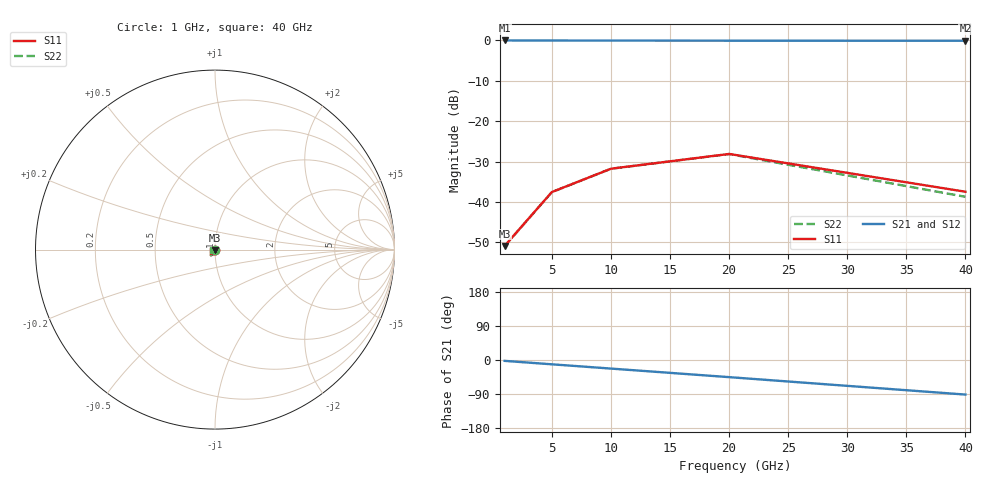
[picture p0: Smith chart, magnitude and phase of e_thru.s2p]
! Generated by circuitRF - EM: EMerge
! circuitRF-EM setup: g_thru_sheets
! circuitRF-EM layout: thru/layout/thru.clay
! circuitRF-EM written: 2026-11-04 17:22:48Z
! circuitRF-EM geometry: 4bac5df9cd719ece
! circuitRF-EM mesh: ae32805cddc33b92
! circuitRF-EM ports: e0915e1a10e1aaad
! circuitRF-EM model: EMerge 3.0.0b2
! Port[1] = port/1
! Port[2] = port/2
! circuitRF-EM port 1: 'port/1' from 'airbox/zmin' to 'Metal1/1', lumped, 50 Ohm
! circuitRF-EM port 2: 'port/2' from 'airbox/zmin' to 'Metal1/1', lumped, 50 Ohm
! circuitRF-EM 3D mesh: 2539 tetrahedra, element order 2
! circuitRF-EM 3D operating temperature: 20 C
! circuitRF-EM 3D run: preset Standard; 2539 tetrahedra; 17990 unknowns; 5 frequency sample(s)
! circuitRF-EM 3D run cost: wall 3 s; EMerge peak memory 1.2 GB
! circuitRF-EM 3D DC row: circuitRF conduction solve of the conductors, 368 elements, 0.17 s; ports as terminal pairs
! circuitRF-EM: re-running the EM setup rewrites this file. If circuitRF reports it as stale, the layout's cross-section changed after this file was written.
# GHz S RI R 50
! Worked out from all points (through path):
!   5 points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, 1 GHz to 40 GHz, reference 50 ohm
!   highest |S21| = 0.00 dB at 1 GHz (marker M1); lowest = -0.1 dB at 40 GHz (marker M2)
!   lowest |S11| = -50.9 dB at 1 GHz (marker M3), VSWR 1.01, Z = 50.2 - j0.23 ohm
!   |S11| at or under -10 dB: start of sweep to end of sweep
!   |S22| runs from -50.9 to -28.1 dB; largest |S21 - S12| = 4.9e-05
1  0.00171 -0.00229  0.9988 -0.04  0.9989 -0.04  0.00168 -0.00229
5  0.00082 -0.0132  0.9783 -0.1966  0.9783 -0.1966  0.000732 -0.0132
10  -0.00539 -0.0252  0.9195 -0.3834  0.9195 -0.3834  -0.00565 -0.0251
20  -0.0229 -0.032  0.6997 -0.7054  0.6998 -0.7054  -0.0236 -0.0313
40  -0.0109 -0.00783  -0.0211 -0.9906  -0.0211 -0.9906  -0.0108 -0.00418
